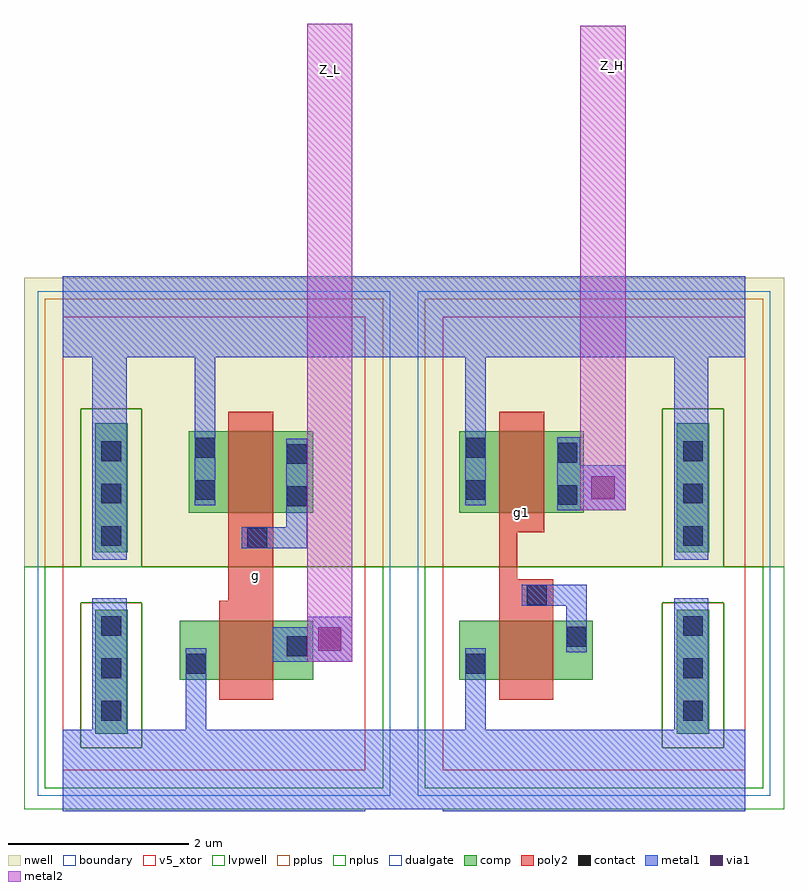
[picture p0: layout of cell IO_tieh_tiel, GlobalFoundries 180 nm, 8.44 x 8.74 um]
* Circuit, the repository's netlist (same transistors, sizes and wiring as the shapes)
* NGSPICE file created from IO_tieh_tiel.ext - technology: gf180mcuD

.subckt gf180mcu_fd_sc_mcu9t5v0__tieh VDD VSS Z VNW VPW a_125_157#
X0 Z a_125_157# VDD VNW pfet_05v0 ad=0.396p pd=2.68u as=0.396p ps=2.68u w=0.9u l=0.5u
X1 a_125_157# a_125_157# VSS VPW nfet_05v0 ad=0.2904p pd=2.2u as=0.2904p ps=2.2u w=0.66u l=0.6u
.ends

.subckt gf180mcu_fd_sc_mcu9t5v0__tiel VDD VSS ZN VNW VPW a_124_157#
X0 ZN a_124_157# VSS VPW nfet_05v0 ad=0.2904p pd=2.2u as=0.2904p ps=2.2u w=0.66u l=0.6u
X1 a_124_157# a_124_157# VDD VNW pfet_05v0 ad=0.396p pd=2.68u as=0.396p ps=2.68u w=0.9u l=0.5u
.ends

.subckt IO_tieh_tiel Z_L Z_H
Xgf180mcu_fd_sc_mcu9t5v0__tieh_0 gf180mcu_fd_sc_mcu9t5v0__tiel_0/VNW VSUBS Z_H gf180mcu_fd_sc_mcu9t5v0__tiel_0/VNW
+ VSUBS g1 gf180mcu_fd_sc_mcu9t5v0__tieh
Xgf180mcu_fd_sc_mcu9t5v0__tiel_0 gf180mcu_fd_sc_mcu9t5v0__tiel_0/VNW VSUBS Z_L gf180mcu_fd_sc_mcu9t5v0__tiel_0/VNW
+ VSUBS g gf180mcu_fd_sc_mcu9t5v0__tiel
.ends

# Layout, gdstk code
import gdstk
lib = gdstk.Library(unit=1e-6, precision=1e-09)
def R(c, l, rs):  # rectangles x0, y0, x1, y1
    for r in rs: c.add(gdstk.rectangle(r[:2], r[2:], *l))
def A(c, l, x, y, w, h, nx, ny, dx, dy):  # array of equal rectangles
    R(c, l, [(x+i*dx, y+j*dy, x+i*dx+w, y+j*dy+h) for i in range(nx) for j in range(ny)])
def P(c, l, *ps):  # polygons
    for p in ps: c.add(gdstk.Polygon(p, *l))
boundary = (0, 0)
nwell = (21, 0)
comp = (22, 0)
poly2 = (30, 0)
pplus = (31, 0)
nplus = (32, 0)
contact = (33, 0)
metal1 = (34, 0)
via1 = (35, 0)
metal2 = (36, 0)
dualgate = (55, 0)
v5_xtor = (112, 1)
lvpwell = (204, 0)

gf180mcu_fd_sc_mcu9t5v0_ = lib.new_cell('gf180mcu_fd_sc_mcu9t5v0__filltie')
R(gf180mcu_fd_sc_mcu9t5v0_, boundary, [(0,0,1.12,5.04)])
R(gf180mcu_fd_sc_mcu9t5v0_, nwell, [(-0.43,2.265,1.55,5.47)])
R(gf180mcu_fd_sc_mcu9t5v0_, comp, [(0.36,0.41,0.72,1.785), (0.36,2.425,0.72,3.855)])
R(gf180mcu_fd_sc_mcu9t5v0_, pplus, [(0.2,0.25,0.88,1.865)])
P(gf180mcu_fd_sc_mcu9t5v0_, pplus, [(-0.2,2.265),(-0.2,5.24),(1.32,5.24),(1.32,2.265),(0.88,2.265),(0.88,4.015),(0.2,4.015),(0.2,2.265)])
P(gf180mcu_fd_sc_mcu9t5v0_, nplus, [(-0.2,-0.2),(-0.2,2.265),(0.2,2.265),(0.2,4.015),(0.88,4.015),(0.88,1.865),(0.2,1.865),(0.2,0.25),(0.88,0.25),(0.88,4.015),(0.88,2.265),(1.32,2.265),(1.32,-0.2)])
A(gf180mcu_fd_sc_mcu9t5v0_, contact, 0.43, 0.555, 0.22, 0.22, 1, 3, 0, 0.47)
A(gf180mcu_fd_sc_mcu9t5v0_, contact, 0.43, 2.495, 0.22, 0.22, 1, 3, 0, 0.47)
P(gf180mcu_fd_sc_mcu9t5v0_, metal1, [(0,-0.45),(0,0.45),(0.33,0.45),(0.33,1.91),(0.71,1.91),(0.71,0.45),(1.12,0.45),(1.12,-0.45)],
  [(0.33,2.34),(0.33,4.59),(0,4.59),(0,5.49),(1.12,5.49),(1.12,4.59),(0.71,4.59),(0.71,2.34)])
R(gf180mcu_fd_sc_mcu9t5v0_, dualgate, [(-0.28,-0.28,1.4,5.32)])
R(gf180mcu_fd_sc_mcu9t5v0_, v5_xtor, [(0,0,1.12,5.04)])
R(gf180mcu_fd_sc_mcu9t5v0_, lvpwell, [(-0.43,-0.43,1.55,2.265)])
gf180mcu_fd_sc_mcu9t5v0_.add(gdstk.Label('VSS', (0.56,-0.45), layer=34, texttype=10))
gf180mcu_fd_sc_mcu9t5v0_.add(gdstk.Label('VDD', (0.56,5.49), layer=34, texttype=10))
gf180mcu_fd_sc_mcu9t5v0_.add(gdstk.Label('& Vendor GLOBALFOUNDRIES', (0,2), layer=63, texttype=63))
gf180mcu_fd_sc_mcu9t5v0_.add(gdstk.Label('& Product GF018hv5v_green_sc9', (0,1.5), layer=63, texttype=63))
gf180mcu_fd_sc_mcu9t5v0_.add(gdstk.Label('& Version 2015q2v2', (0,1), layer=63, texttype=63))
gf180mcu_fd_sc_mcu9t5v0_.add(gdstk.Label('& Metric 1.00', (0,0.5), layer=63, texttype=63))

via_dev = lib.new_cell('via_dev')
R(via_dev, metal1, [(0,0,0.5,0.5)])
R(via_dev, via1, [(0.12,0.12,0.38,0.38)])
R(via_dev, metal2, [(0,0,0.5,0.5)])

c_gf180mcu_fd_sc_mcu9t5v0_ = lib.new_cell('gf180mcu_fd_sc_mcu9t5v0__tiel')
R(c_gf180mcu_fd_sc_mcu9t5v0_, boundary, [(0,0,2.24,5.04)])
R(c_gf180mcu_fd_sc_mcu9t5v0_, nwell, [(-0.43,2.265,2.67,5.47)])
R(c_gf180mcu_fd_sc_mcu9t5v0_, comp, [(0.18,1.005,1.66,1.665), (0.28,2.865,1.66,3.765)])
P(c_gf180mcu_fd_sc_mcu9t5v0_, poly2, [(0.62,0.785),(0.62,1.885),(0.72,1.885),(0.72,3.985),(1.22,3.985),(1.22,0.785)])
R(c_gf180mcu_fd_sc_mcu9t5v0_, pplus, [(-0.2,2.265,2.44,5.24)])
R(c_gf180mcu_fd_sc_mcu9t5v0_, nplus, [(-0.2,-0.2,2.44,2.265)])
R(c_gf180mcu_fd_sc_mcu9t5v0_, contact, [(0.25,1.075,0.47,1.295), (1.37,1.27,1.59,1.49), (0.93,2.475,1.15,2.695), (1.37,2.935,1.59,3.155), (0.35,3.005,0.57,3.225), (1.37,3.405,1.59,3.625), (0.35,3.475,0.57,3.695)])
R(c_gf180mcu_fd_sc_mcu9t5v0_, metal1, [(1.215,1.21,1.595,1.59)])
P(c_gf180mcu_fd_sc_mcu9t5v0_, metal1, [(0.87,2.47),(0.87,2.7),(1.365,2.7),(1.365,3.685),(1.595,3.685),(1.595,2.47)],
  [(0,-0.45),(0,0.45),(0.245,0.45),(0.245,1.355),(0.475,1.355),(0.475,0.45),(2.24,0.45),(2.24,-0.45)],
  [(0.345,2.945),(0.345,4.59),(0,4.59),(0,5.49),(2.24,5.49),(2.24,4.59),(0.575,4.59),(0.575,2.945)])
R(c_gf180mcu_fd_sc_mcu9t5v0_, dualgate, [(-0.28,-0.28,2.52,5.32)])
R(c_gf180mcu_fd_sc_mcu9t5v0_, v5_xtor, [(0,0,2.24,5.04)])
R(c_gf180mcu_fd_sc_mcu9t5v0_, lvpwell, [(-0.43,-0.43,2.67,2.265)])
c_gf180mcu_fd_sc_mcu9t5v0_.add(gdstk.Label('VDD', (1.12,5.49), layer=34, texttype=10))
c_gf180mcu_fd_sc_mcu9t5v0_.add(gdstk.Label('VSS', (1.12,-0.45), layer=34, texttype=10))
c_gf180mcu_fd_sc_mcu9t5v0_.add(gdstk.Label('ZN', (1.4,1.4), layer=34, texttype=10))
c_gf180mcu_fd_sc_mcu9t5v0_.add(gdstk.Label('& Vendor GLOBALFOUNDRIES', (0,2), layer=63, texttype=63))
c_gf180mcu_fd_sc_mcu9t5v0_.add(gdstk.Label('& Product GF018hv5v_green_sc9', (0,1.5), layer=63, texttype=63))
c_gf180mcu_fd_sc_mcu9t5v0_.add(gdstk.Label('& Version 2015q2v2', (0,1), layer=63, texttype=63))
c_gf180mcu_fd_sc_mcu9t5v0_.add(gdstk.Label('& Metric 1.00', (0,0.5), layer=63, texttype=63))
c_gf180mcu_fd_sc_mcu9t5v0_.add(gdstk.Label('VNW', (0.345,3.92), layer=21, texttype=10))
c_gf180mcu_fd_sc_mcu9t5v0_.add(gdstk.Label('VPW', (0.34,-0.085), layer=204, texttype=10))

c_gf180mcu_fd_sc_mcu9t5v0__ = lib.new_cell('gf180mcu_fd_sc_mcu9t5v0__tieh')
R(c_gf180mcu_fd_sc_mcu9t5v0__, boundary, [(0,0,2.24,5.04)])
R(c_gf180mcu_fd_sc_mcu9t5v0__, nwell, [(-0.43,2.265,2.67,5.47)])
R(c_gf180mcu_fd_sc_mcu9t5v0__, comp, [(0.185,1.005,1.665,1.665), (0.185,2.865,1.565,3.765)])
P(c_gf180mcu_fd_sc_mcu9t5v0__, poly2, [(0.625,0.785),(0.625,3.985),(1.125,3.985),(1.125,2.645),(0.825,2.645),(0.825,2.125),(1.225,2.125),(1.225,0.785)])
R(c_gf180mcu_fd_sc_mcu9t5v0__, pplus, [(-0.2,2.265,2.44,5.24)])
R(c_gf180mcu_fd_sc_mcu9t5v0__, nplus, [(-0.2,-0.2,2.44,2.265)])
R(c_gf180mcu_fd_sc_mcu9t5v0__, contact, [(0.255,1.075,0.475,1.295), (1.375,1.375,1.595,1.595), (0.935,1.835,1.155,2.055), (1.275,2.95,1.495,3.17), (0.255,3.005,0.475,3.225), (1.275,3.42,1.495,3.64), (0.255,3.475,0.475,3.695)])
R(c_gf180mcu_fd_sc_mcu9t5v0__, metal1, [(1.27,2.89,1.53,3.7)])
P(c_gf180mcu_fd_sc_mcu9t5v0__, metal1, [(1.37,1.315),(1.37,1.83),(0.875,1.83),(0.875,2.06),(1.6,2.06),(1.6,1.315)],
  [(0,-0.45),(0,0.45),(0.25,0.45),(0.25,1.355),(0.48,1.355),(0.48,0.45),(2.24,0.45),(2.24,-0.45)],
  [(0.25,2.945),(0.25,4.59),(0,4.59),(0,5.49),(2.24,5.49),(2.24,4.59),(0.48,4.59),(0.48,2.945)])
R(c_gf180mcu_fd_sc_mcu9t5v0__, dualgate, [(-0.28,-0.28,2.52,5.32)])
R(c_gf180mcu_fd_sc_mcu9t5v0__, v5_xtor, [(0,0,2.24,5.04)])
R(c_gf180mcu_fd_sc_mcu9t5v0__, lvpwell, [(-0.43,-0.43,2.67,2.265)])
c_gf180mcu_fd_sc_mcu9t5v0__.add(gdstk.Label('VDD', (1.12,5.49), layer=34, texttype=10))
c_gf180mcu_fd_sc_mcu9t5v0__.add(gdstk.Label('VSS', (1.12,-0.45), layer=34, texttype=10))
c_gf180mcu_fd_sc_mcu9t5v0__.add(gdstk.Label('Z', (1.4,3.08), layer=34, texttype=10))
c_gf180mcu_fd_sc_mcu9t5v0__.add(gdstk.Label('& Vendor GLOBALFOUNDRIES', (0,2), layer=63, texttype=63))
c_gf180mcu_fd_sc_mcu9t5v0__.add(gdstk.Label('& Product GF018hv5v_green_sc9', (0,1.5), layer=63, texttype=63))
c_gf180mcu_fd_sc_mcu9t5v0__.add(gdstk.Label('& Version 2015q2v2', (0,1), layer=63, texttype=63))
c_gf180mcu_fd_sc_mcu9t5v0__.add(gdstk.Label('& Metric 1.00', (0,0.5), layer=63, texttype=63))
c_gf180mcu_fd_sc_mcu9t5v0__.add(gdstk.Label('VNW', (0.345,3.92), layer=21, texttype=10))
c_gf180mcu_fd_sc_mcu9t5v0__.add(gdstk.Label('VPW', (0.34,-0.085), layer=204, texttype=10))

io_tieh_tiel = lib.new_cell('IO_tieh_tiel')
R(io_tieh_tiel, metal1, [(-2.455,-0.875,-1.485,0.005), (-3.38,4.145,-1.595,5.045)])
R(io_tieh_tiel, metal2, [(-3.1,0.765,-2.6,7.845), (-0.065,2.445,0.435,7.825)])
io_tieh_tiel.add(gdstk.Reference(gf180mcu_fd_sc_mcu9t5v0_, (-5.815,-0.445)))
io_tieh_tiel.add(gdstk.Reference(gf180mcu_fd_sc_mcu9t5v0_, (0.645,-0.445)))
io_tieh_tiel.add(gdstk.Reference(via_dev, (-3.1,0.765)))
io_tieh_tiel.add(gdstk.Reference(via_dev, (-0.065,2.445)))
io_tieh_tiel.add(gdstk.Reference(c_gf180mcu_fd_sc_mcu9t5v0_, (-4.695,-0.445)))
io_tieh_tiel.add(gdstk.Reference(c_gf180mcu_fd_sc_mcu9t5v0__, (-1.595,-0.445)))
io_tieh_tiel.add(gdstk.Label('Z_L', (-2.84,7.34), layer=36, texttype=10))
io_tieh_tiel.add(gdstk.Label('Z_H', (0.29,7.38), layer=36, texttype=10))
io_tieh_tiel.add(gdstk.Label('g', (-3.67,1.72), layer=30, texttype=10))
io_tieh_tiel.add(gdstk.Label('g1', (-0.72,2.42), layer=30, texttype=10))

lib.write_gds('IO_tieh_tiel.gds')
